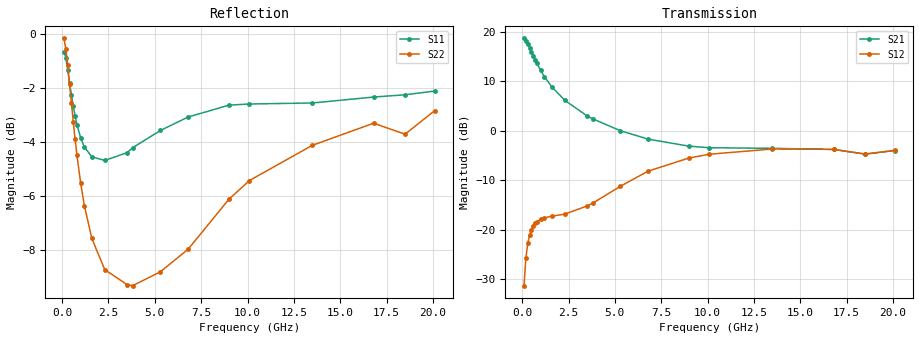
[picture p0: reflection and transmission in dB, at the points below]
!  Infineon Technologies AG
! BFR380L3 , PF131585-7, No.6, Th 09.10.01, soldered on pcb-board, measured with PP GSG850
!  Vce=5.0 V,  Ic=2.5 mA
! Common Emitter S-Parameters:  15. November 2001
#  GHz  S  MA  R  50
! f  S11  S21  S12  S22
! GHz  Mag  Ang  Mag  Ang  Mag  Ang  Mag  Ang
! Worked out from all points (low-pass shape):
!   201 points, 100 MHz to 20.1 GHz, reference 50 ohm
!   highest |S21| = 18.72 dB at 100 MHz (marker M1); lowest = -4.7 dB at 18.5 GHz (marker M2)
!   |S21| within 3 dB of the highest: start of sweep to 535.1 MHz
!   lowest |S11| = -4.7 dB at 2.3 GHz (marker M3), VSWR 3.79, Z = 13.2 - j0.905 ohm
!   |S11| at or under -10 dB: nowhere
!   |S22| runs from -9.3 to -0.2 dB; largest |S21 - S12| = 8.6
!   S11 on the Smith chart (normalised r, x): 100 MHz: 1.46, -5.92; 500 MHz: 0.31, -1.17; 1.2 GHz: 0.27, -0.38; 3.8 GHz: 0.26, +0.26; 9 GHz: 0.32, +1.04; 20.1 GHz: 0.99, +2.51
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0.1  0.9263 -18.1  8.627 167.3  0.0271 80.4  0.9808 -9.5
0.2  0.9023 -35.4  8.111 155.7  0.05167 70.3  0.9376 -18.4
0.3  0.8585 -51.7  7.551 145.1  0.07247 62.1  0.8754 -26.0
0.4  0.8114 -65.9  6.931 135.8  0.08786 55.1  0.8084 -32.3
0.5  0.7716 -78.7  6.314 127.8  0.09989 49.7  0.7455 -37.4
0.6  0.7336 -89.8  5.744 120.9  0.1089 45.3  0.6878 -41.4
0.7  0.704 -99.6  5.249 114.9  0.1156 41.9  0.6382 -44.6
0.8  0.6786 -108.6  4.804 109.7  0.1206 39.2  0.5956 -47.4
1  0.6411 -123.3  4.085 100.9  0.1275 35.3  0.5289 -51.4
1.2  0.6169 -135.4  3.536 93.6  0.1319 33.2  0.4806 -54.5
1.6  0.5918 -154.3  2.786 81.7  0.1368 31.8  0.4179 -59.7
2.3  0.5827 -177.8  2.036 65.7  0.1438 34.8  0.3657 -68.5
3.5  0.6022 154.8  1.417 44.9  0.1736 45.4  0.3431 -87.2
3.8  0.615 149.5  1.324 40.7  0.1851 47.6  0.3415 -93.2
5.3  0.6621 125.7  1.002 22.7  0.275 50.6  0.3623 -123.5
6.8  0.7013 106.2  0.8236 10.8  0.3915 43.6  0.3991 -155.9
8.999999  0.7377 84.9  0.7001 0.4  0.531 26.7  0.4939 164.1
10.1  0.7413 76.4  0.6748 -3.3  0.5798 17.8  0.5347 146.6
13.5  0.7445 58.6  0.6652 -17.0  0.6551 -7.0  0.6216 107.0
16.8  0.7636 47.2  0.648 -29.5  0.6501 -24.5  0.6829 81.2
18.5  0.771 45.6  0.5821 -37.2  0.5825 -33.1  0.6517 74.6
20.1  0.7833 38.6  0.6318 -41.5  0.6353 -38.5  0.7208 63.2
